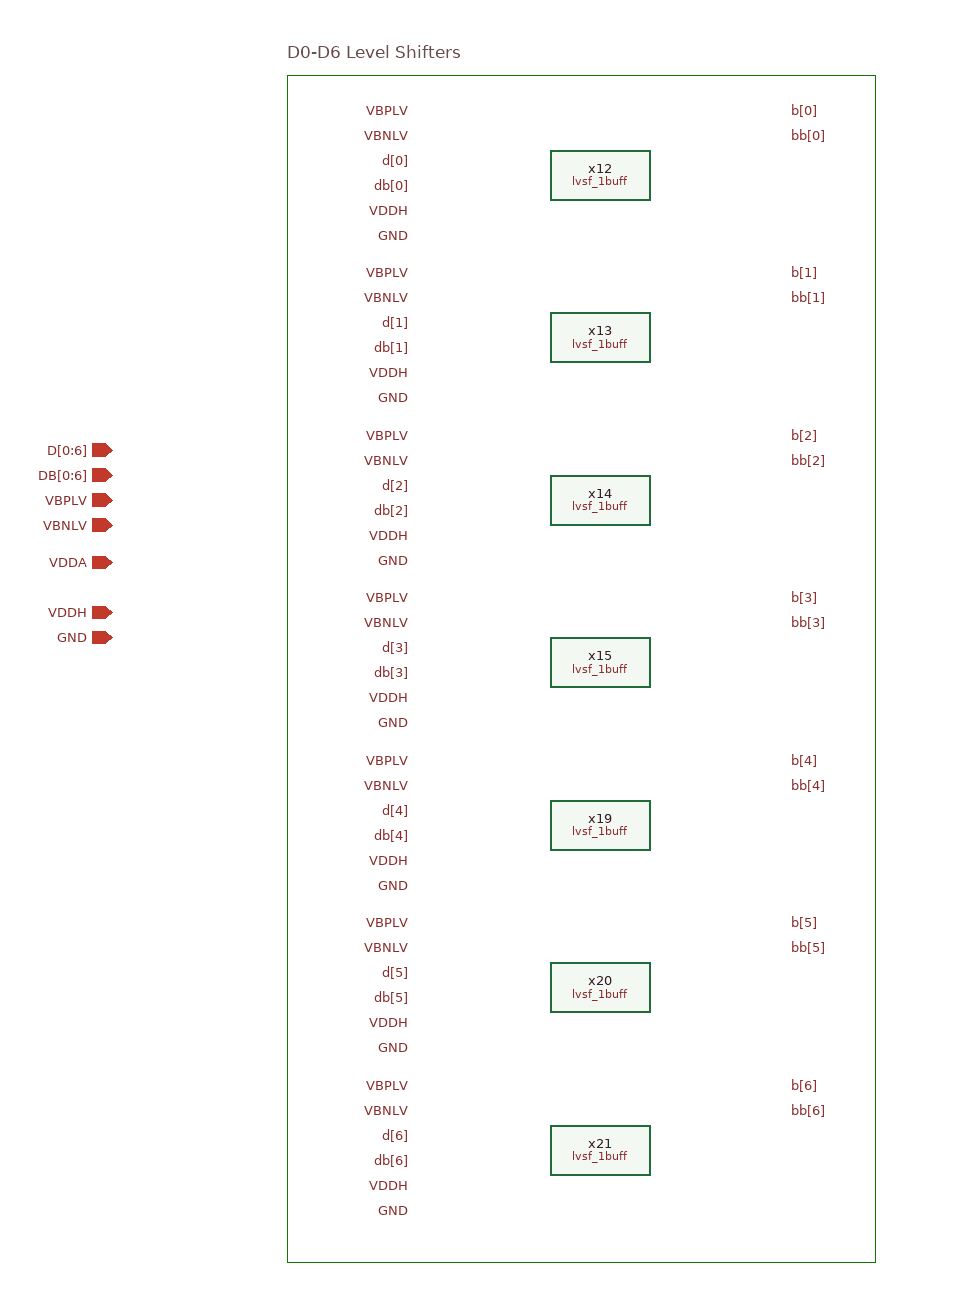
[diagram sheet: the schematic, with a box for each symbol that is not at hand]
v {xschem version=3.4.8RC file_version=1.2}
G {}
K {}
V {}
S {}
E {}
P 4 5 300 -120 770 -120 770 -1070 300 -1070 300 -120 {}
T {D0-D6 Level Shifters} 300 -1100 0 0 0.4 0.4 {}
C {lvsf_1buff.sym} 550 -990 0 0 {name=x12}
C {devices/lab_pin.sym} 400 -1040 0 0 {name=p52 sig_type=std_logic lab=VBPLV}
C {devices/lab_pin.sym} 400 -1020 0 0 {name=p53 sig_type=std_logic lab=VBNLV}
C {devices/lab_pin.sym} 400 -1000 0 0 {name=p54 sig_type=std_logic lab=d[0]}
C {devices/lab_pin.sym} 400 -980 0 0 {name=p55 sig_type=std_logic lab=db[0]}
C {devices/lab_pin.sym} 400 -960 0 0 {name=p56 sig_type=std_logic lab=VDDH}
C {devices/lab_pin.sym} 400 -940 0 0 {name=p57 sig_type=std_logic lab=GND}
C {devices/lab_pin.sym} 700 -1040 0 1 {name=p58 sig_type=std_logic lab=b[0]}
C {devices/lab_pin.sym} 700 -1020 0 1 {name=p59 sig_type=std_logic lab=bb[0]}
C {lvsf_1buff.sym} 550 -860 0 0 {name=x13}
C {devices/lab_pin.sym} 400 -910 0 0 {name=p60 sig_type=std_logic lab=VBPLV}
C {devices/lab_pin.sym} 400 -890 0 0 {name=p61 sig_type=std_logic lab=VBNLV}
C {devices/lab_pin.sym} 400 -870 0 0 {name=p62 sig_type=std_logic lab=d[1]}
C {devices/lab_pin.sym} 400 -850 0 0 {name=p63 sig_type=std_logic lab=db[1]}
C {devices/lab_pin.sym} 400 -830 0 0 {name=p64 sig_type=std_logic lab=VDDH}
C {devices/lab_pin.sym} 400 -810 0 0 {name=p65 sig_type=std_logic lab=GND}
C {devices/lab_pin.sym} 700 -910 0 1 {name=p66 sig_type=std_logic lab=b[1]}
C {devices/lab_pin.sym} 700 -890 0 1 {name=p67 sig_type=std_logic lab=bb[1]}
C {lvsf_1buff.sym} 550 -730 0 0 {name=x14}
C {devices/lab_pin.sym} 400 -780 0 0 {name=p68 sig_type=std_logic lab=VBPLV}
C {devices/lab_pin.sym} 400 -760 0 0 {name=p69 sig_type=std_logic lab=VBNLV}
C {devices/lab_pin.sym} 400 -740 0 0 {name=p70 sig_type=std_logic lab=d[2]}
C {devices/lab_pin.sym} 400 -720 0 0 {name=p71 sig_type=std_logic lab=db[2]}
C {devices/lab_pin.sym} 400 -700 0 0 {name=p72 sig_type=std_logic lab=VDDH}
C {devices/lab_pin.sym} 400 -680 0 0 {name=p73 sig_type=std_logic lab=GND}
C {devices/lab_pin.sym} 700 -780 0 1 {name=p74 sig_type=std_logic lab=b[2]}
C {devices/lab_pin.sym} 700 -760 0 1 {name=p75 sig_type=std_logic lab=bb[2]}
C {lvsf_1buff.sym} 550 -600 0 0 {name=x15}
C {devices/lab_pin.sym} 400 -650 0 0 {name=p76 sig_type=std_logic lab=VBPLV}
C {devices/lab_pin.sym} 400 -630 0 0 {name=p77 sig_type=std_logic lab=VBNLV}
C {devices/lab_pin.sym} 400 -610 0 0 {name=p78 sig_type=std_logic lab=d[3]}
C {devices/lab_pin.sym} 400 -590 0 0 {name=p79 sig_type=std_logic lab=db[3]}
C {devices/lab_pin.sym} 400 -570 0 0 {name=p80 sig_type=std_logic lab=VDDH}
C {devices/lab_pin.sym} 400 -550 0 0 {name=p81 sig_type=std_logic lab=GND}
C {devices/lab_pin.sym} 700 -650 0 1 {name=p82 sig_type=std_logic lab=b[3]}
C {devices/lab_pin.sym} 700 -630 0 1 {name=p83 sig_type=std_logic lab=bb[3]}
C {lvsf_1buff.sym} 550 -470 0 0 {name=x19}
C {devices/lab_pin.sym} 400 -520 0 0 {name=p143 sig_type=std_logic lab=VBPLV}
C {devices/lab_pin.sym} 400 -500 0 0 {name=p144 sig_type=std_logic lab=VBNLV}
C {devices/lab_pin.sym} 400 -480 0 0 {name=p145 sig_type=std_logic lab=d[4]}
C {devices/lab_pin.sym} 400 -460 0 0 {name=p146 sig_type=std_logic lab=db[4]}
C {devices/lab_pin.sym} 400 -440 0 0 {name=p147 sig_type=std_logic lab=VDDH}
C {devices/lab_pin.sym} 400 -420 0 0 {name=p148 sig_type=std_logic lab=GND}
C {devices/lab_pin.sym} 700 -520 0 1 {name=p149 sig_type=std_logic lab=b[4]}
C {devices/lab_pin.sym} 700 -500 0 1 {name=p150 sig_type=std_logic lab=bb[4]}
C {lvsf_1buff.sym} 550 -340 0 0 {name=x20}
C {devices/lab_pin.sym} 400 -390 0 0 {name=p151 sig_type=std_logic lab=VBPLV}
C {devices/lab_pin.sym} 400 -370 0 0 {name=p152 sig_type=std_logic lab=VBNLV}
C {devices/lab_pin.sym} 400 -350 0 0 {name=p153 sig_type=std_logic lab=d[5]}
C {devices/lab_pin.sym} 400 -330 0 0 {name=p154 sig_type=std_logic lab=db[5]}
C {devices/lab_pin.sym} 400 -310 0 0 {name=p155 sig_type=std_logic lab=VDDH}
C {devices/lab_pin.sym} 400 -290 0 0 {name=p156 sig_type=std_logic lab=GND}
C {devices/lab_pin.sym} 700 -390 0 1 {name=p157 sig_type=std_logic lab=b[5]}
C {devices/lab_pin.sym} 700 -370 0 1 {name=p158 sig_type=std_logic lab=bb[5]}
C {lvsf_1buff.sym} 550 -210 0 0 {name=x21}
C {devices/lab_pin.sym} 400 -260 0 0 {name=p159 sig_type=std_logic lab=VBPLV}
C {devices/lab_pin.sym} 400 -240 0 0 {name=p160 sig_type=std_logic lab=VBNLV}
C {devices/lab_pin.sym} 400 -220 0 0 {name=p161 sig_type=std_logic lab=d[6]}
C {devices/lab_pin.sym} 400 -200 0 0 {name=p162 sig_type=std_logic lab=db[6]}
C {devices/lab_pin.sym} 400 -180 0 0 {name=p163 sig_type=std_logic lab=VDDH}
C {devices/lab_pin.sym} 400 -160 0 0 {name=p164 sig_type=std_logic lab=GND}
C {devices/lab_pin.sym} 700 -260 0 1 {name=p165 sig_type=std_logic lab=b[6]}
C {devices/lab_pin.sym} 700 -240 0 1 {name=p166 sig_type=std_logic lab=bb[6]}
C {devices/title.sym} 160 -40 0 0 {name=l3 author="Yohanes Stefanus"}
C {devices/ipin.sym} 160 -620 0 0 {name=p20 lab=GND}
C {devices/ipin.sym} 160 -770 0 0 {name=p1 lab=D[0:6]}
C {devices/ipin.sym} 160 -710 0 0 {name=p2 lab=VBNLV}
C {devices/ipin.sym} 160 -640 0 0 {name=p3 lab=VDDH}
C {devices/ipin.sym} 160 -680 0 0 {name=p4 lab=VDDA}
C {devices/ipin.sym} 160 -750 0 0 {name=p142 lab=DB[0:6]}
C {devices/ipin.sym} 160 -730 0 0 {name=p171 lab=VBPLV}
